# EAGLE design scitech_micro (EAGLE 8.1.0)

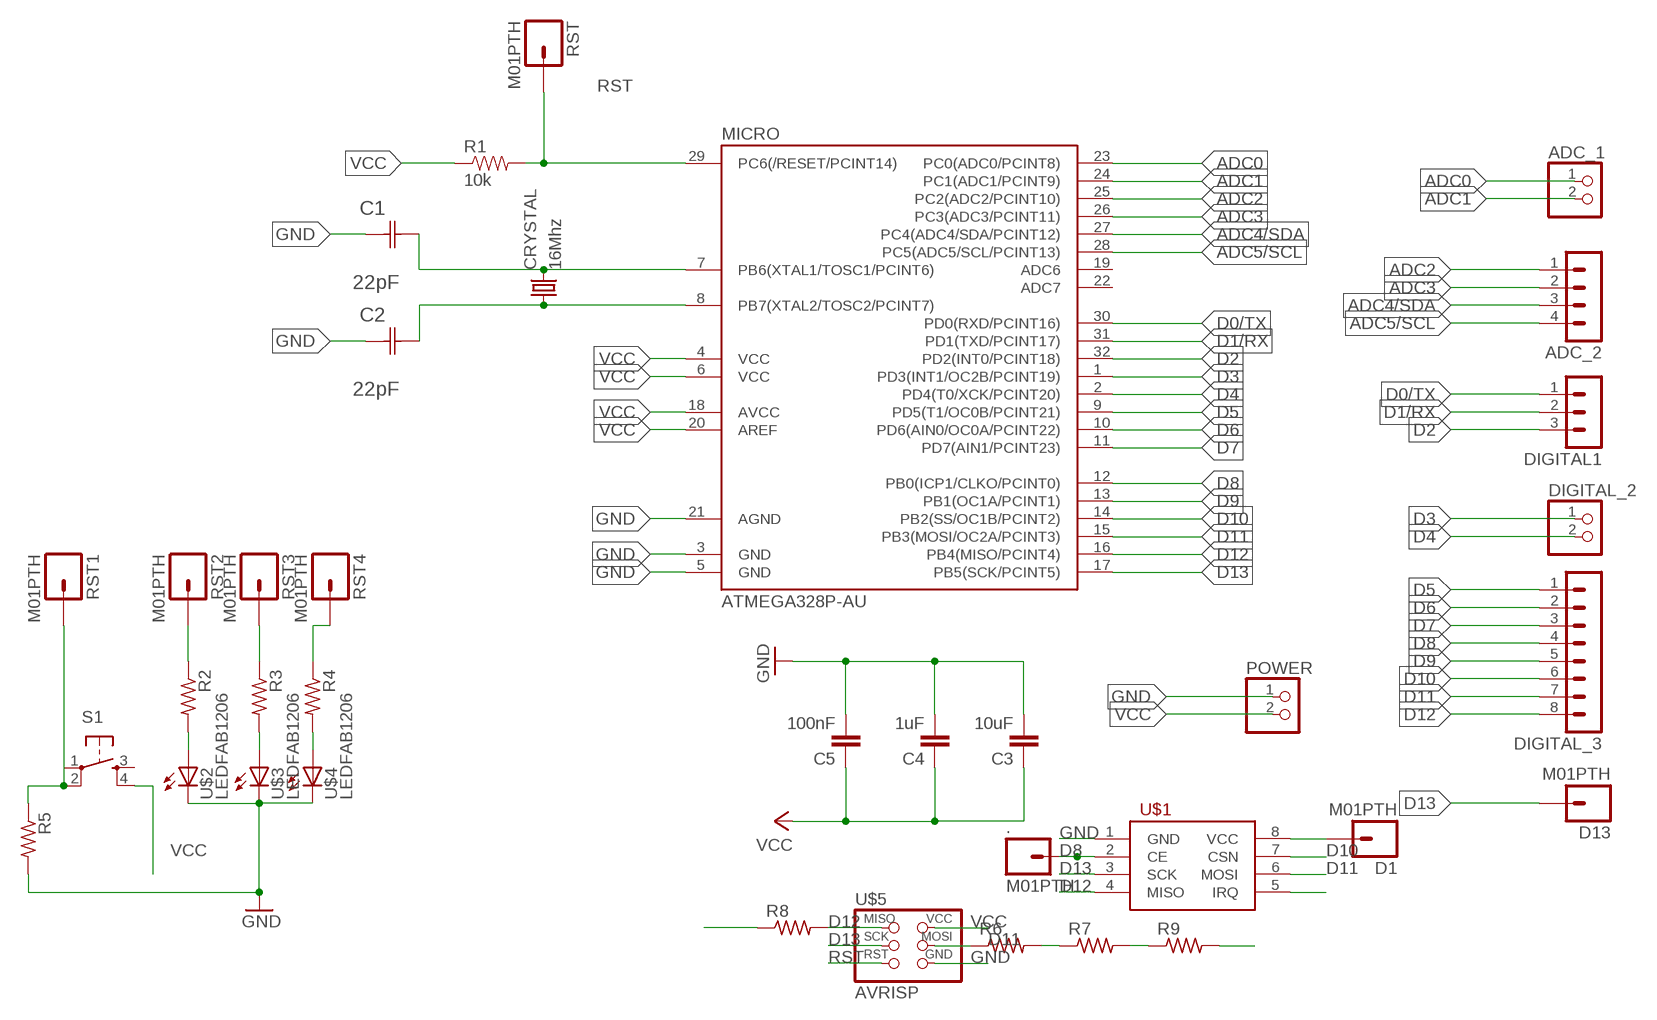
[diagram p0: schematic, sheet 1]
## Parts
.  M01PTH  [1X01]
ADC_1  PINHD-1X2  [1X02]
ADC_2  MA04-1  [MA04-1]
C1  22pF  0612ZC225MAT2A  [CAPC3216X178N]
C2  22pF  0612ZC225MAT2A  [CAPC3216X178N]
C3  10uF  CAP1206  [1206]
C4  1uF  CAP1206  [1206]
C5  100nF  CAP1206  [1206]
CRYSTAL  16Mhz  CSM-7X-DU  [CSM-7X-DU]
D1  M01PTH  [1X01]
D13  M01PTH  [1X01]
DIGITAL1  MA03-1  [MA03-1]
DIGITAL_2  PINHD-1X2  [1X02]
DIGITAL_3  MA08-1  [MA08-1]
MICRO  ATMEGA328P-AU  ATMEGA48/88/168-AU  [TQFP32-08]
POWER  PINHD-1X2  [1X02]
R1  10k  RESISTOR1206  [1206]
R2  RES-US1206FAB  [R1206FAB]
R3  RES-US1206FAB  [R1206FAB]
R4  RES-US1206FAB  [R1206FAB]
R5  RES-US1206FAB  [R1206FAB]
R6  RES-US1206FAB  [R1206FAB]
R7  RES-US1206FAB  [R1206FAB]
R8  RES-US1206FAB  [R1206FAB]
R9  RES-US1206FAB  [R1206FAB]
RST  M01PTH  [1X01]
RST1  M01PTH  [1X01]
RST2  M01PTH  [1X01]
RST3  M01PTH  [1X01]
RST4  M01PTH  [1X01]
S1  6MM_SWITCH6MM_SWITCH  [6MM_SWITCH]
U$1  NRF24L01+  [2X04_THRU]
U$2  LEDFAB1206  [LED1206FAB]
U$3  LEDFAB1206  [LED1206FAB]
U$4  LEDFAB1206  [LED1206FAB]
U$5  AVRISP  [2X03]

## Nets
ADC0: ADC_1.1 MICRO.23(PC0(ADC0/PCINT8))
ADC1: ADC_1.2 MICRO.24(PC1(ADC1/PCINT9))
ADC2: ADC_2.1 MICRO.25(PC2(ADC2/PCINT10))
ADC3: ADC_2.2 MICRO.26(PC3(ADC3/PCINT11))
ADC4/SDA: ADC_2.3 MICRO.27(PC4(ADC4/SDA/PCINT12))
ADC5/SCL: ADC_2.4 MICRO.28(PC5(ADC5/SCL/PCINT13))
D0/TX: DIGITAL1.1 MICRO.30(PD0(RXD/PCINT16))
D1/RX: DIGITAL1.2 MICRO.31(PD1(TXD/PCINT17))
D2: DIGITAL1.3 MICRO.32(PD2(INT0/PCINT18))
D3: DIGITAL_2.1 MICRO.1(PD3(INT1/OC2B/PCINT19))
D4: DIGITAL_2.2 MICRO.2(PD4(T0/XCK/PCINT20))
D5: DIGITAL_3.1 MICRO.9(PD5(T1/OC0B/PCINT21))
D6: DIGITAL_3.2 MICRO.10(PD6(AIN0/OC0A/PCINT22))
D7: DIGITAL_3.3 MICRO.11(PD7(AIN1/PCINT23))
D8: ..1 DIGITAL_3.4 MICRO.12(PB0(ICP1/CLKO/PCINT0)) U$1.2(CE)
D9: DIGITAL_3.5 MICRO.13(PB1(OC1A/PCINT1))
D10: DIGITAL_3.6 MICRO.14(PB2(SS/OC1B/PCINT2)) U$1.7(CSN)
D11: DIGITAL_3.7 MICRO.15(PB3(MOSI/OC2A/PCINT3)) R6.1 R9.2 U$1.6(MOSI) U$5.4(MOSI)
D12: DIGITAL_3.8 MICRO.16(PB4(MISO/PCINT4)) R8.1 R8.2 U$1.4(MISO) U$5.1(MISO)
D13: D13.1 MICRO.17(PB5(SCK/PCINT5)) U$1.3(SCK) U$5.3(SCK)
GND: C1.1(C1) C2.1(C1) C3.2 C4.2 C5.2 MICRO.3(GND) MICRO.5(GND) MICRO.21(AGND) POWER.1 R5.2 U$1.1(GND) U$2.2(C) U$3.2(C) U$4.2(C) U$5.6(GND)
N$1: R2.1 RST2.1
N$2: C1.2(C2) CRYSTAL.2 MICRO.7(PB6(XTAL1/TOSC1/PCINT6))
N$3: R6.2 R7.1
N$4: R3.1 RST3.1
N$5: R4.1 RST4.1
N$6: R2.2 U$2.1(A)
N$7: R3.2 U$3.1(A)
N$8: R4.2 U$4.1(A)
N$9: C2.2(C2) CRYSTAL.1 MICRO.8(PB7(XTAL2/TOSC2/PCINT7))
N$10: R5.1 RST1.1 S1.2(P1)
N$11: R7.2 R9.1
N$15: D1.1 U$1.8(VCC)
N$18: U$1.5(IRQ)
RST: MICRO.29(PC6(/RESET/PCINT14)) R1.2 RST.1 U$5.5(RST)
VCC: C3.1 C4.1 C5.1 MICRO.4(VCC) MICRO.6(VCC) MICRO.18(AVCC) MICRO.20(AREF) POWER.2 R1.1 S1.4(S1) U$5.2(VCC)
Unconnected: MICRO.19(ADC6) MICRO.22(ADC7) S1.1(P) S1.3(S)

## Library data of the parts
. D1 D13 RST RST1-RST4 = 01_SparkFun:M01: Header 1
ADC_1 DIGITAL_2 POWER = pinhead:PINHD-1X2: PIN HEADER
ADC_2 = con-lstb:MA04-1: PIN HEADER; OC_FARNELL: unknown; OC_NEWARK: unknown
C1 C2 = AVX_By_element14_Batch_1:0612ZC225MAT2A: Capacitor 1206; MPN: 0612ZC225MAT2A; OC_FARNELL: -; OC_NEWARK: 12N3209; SUPPLIER: AVX; TOLERANCE: ±20%; VALUE: 2.2µF; VOLTAGERATING: 10V
C3-C5 = 01_SparkFun:CAP: Capacitor
CRYSTAL = 01_FAB_Hello:CSM-7X-DU: SMD CRYSTAL; OC_FARNELL: unknown; OC_NEWARK: unknown
DIGITAL1 = con-lstb:MA03-1: PIN HEADER; OC_FARNELL: unknown; OC_NEWARK: unknown
DIGITAL_3 = con-lstb:MA08-1: PIN HEADER; OC_FARNELL: unknown; OC_NEWARK: unknown
MICRO = atmega8:ATMEGA48/88/168
R1 = 01_SparkFun:RESISTOR: Resistor
R2-R9 = fab:RES-US: Resistor (US Symbol)
S1 = fab:6MM_SWITCH: OMRON SWITCH
U$1 = fab:NRF24L01+: nRF24L01+ 2.4GHz Wireless Transceiver module
U$2-U$4 = fab:LED: LED
U$5 = fab:AVRISP

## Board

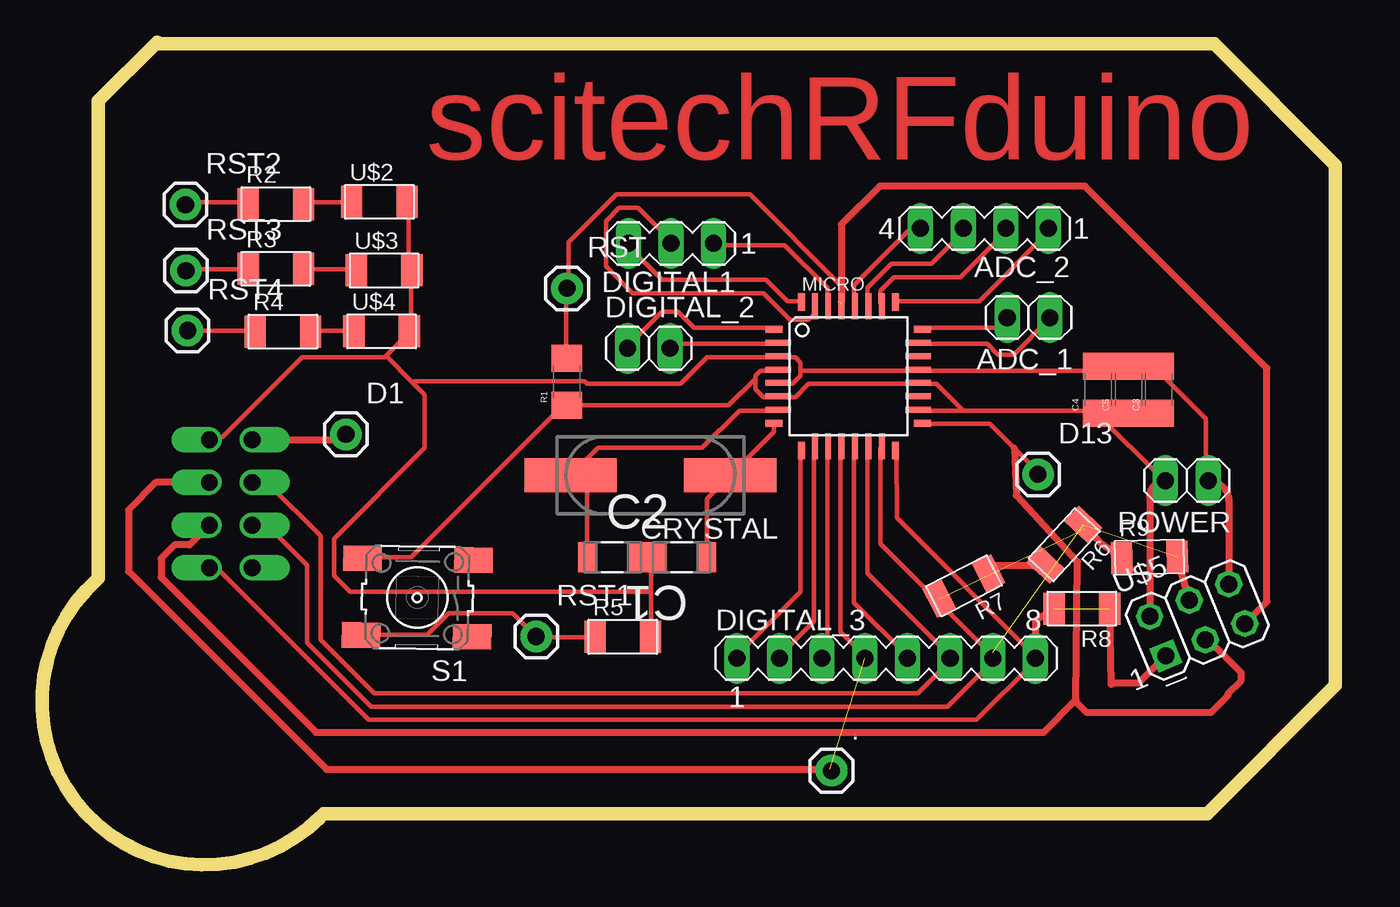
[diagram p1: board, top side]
Size 77.02 x 48.98 mm. Coordinates in mm from the lower left corner, seen from the top.
Outline: 6.85,48.87 69.8,48.87 77.02,41.66 77.02,10.7 69.38,3.06 16.78,3.06 16.56,2.84 arc-184 3.36,17.06 3.36,45.49 6.85,48.98
Copper layers (1*16): Top 0.035mm / dielectric 1.5mm / Bottom 0.035mm
Design rules "default *": minimum track width 10mil, minimum drill 24mil, track to track 16mil, track to pad 16mil, pad to pad 16mil, via to via 16mil, smd to smd 8mil, copper to edge 40mil, drill to drill 16mil, minimum pad ring 10mil, minimum via ring 8mil, stop-mask expansion 4mil, vias tented up to drill 0mil, thermal gap 10mil

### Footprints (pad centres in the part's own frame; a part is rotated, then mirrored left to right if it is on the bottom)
1X01 = drill 1.016 pad 1.88: 1 0,0
1X02 = drill 1.016 long: 1 -1.27,0; 2 1.27,0
MA04-1 = drill 1.016 long: 1 -3.81,0; 2 -1.27,0; 3 1.27,0; 4 3.81,0
CAPC3216X178N = smd 1.118 x 1.803: 1 -1.499,0; 2 1.499,0
1206 = smd 1.6 x 1.8: 1 -1.4,0; 2 1.4,0
CSM-7X-DU = smd 5.5 x 2: 1 -4.75,0; 2 4.75,0
MA03-1 = drill 1.016 long: 1 -2.54,0; 2 0,0; 3 2.54,0
MA08-1 = drill 1.016 long: 1 -8.89,0; 2 -6.35,0; 3 -3.81,0; 4 -1.27,0; 5 1.27,0; 6 3.81,0; 7 6.35,0; 8 8.89,0
TQFP32-08 = smd 1.016 x 0.406: 1 -4.42,2.8; 8 -4.42,-2.8; 17 4.42,-2.8; 24 4.42,2.8 | smd 1.524 x 0.356: 2 -4.166,2; 3 -4.166,1.2; 4 -4.166,0.4; 5 -4.166,-0.4; 6 -4.166,-1.2; 7 -4.166,-2; 18 4.166,-2; 19 4.166,-1.2; 20 4.166,-0.4; 21 4.166,0.4; 22 4.166,1.2; 23 4.166,2 | smd 0.406 x 1.016: 9 -2.8,-4.42; 16 2.8,-4.42; 25 2.8,4.42; 32 -2.8,4.42 | smd 0.356 x 1.524: 10 -2,-4.166; 11 -1.2,-4.166; 12 -0.4,-4.166; 13 0.4,-4.166; 14 1.2,-4.166; 15 2,-4.166; 26 2,4.166; 27 1.2,4.166; 28 0.4,4.166; 29 -0.4,4.166; 30 -1.2,4.166; 31 -2,4.166
R1206FAB = smd 1.27 x 1.905: 1 -1.651,0; 2 1.651,0
6MM_SWITCH = smd 2.286 x 1.524: 1 -3.302,2.286; 2 3.302,2.286; 3 -3.302,-2.286; 4 3.302,-2.286
2X04_THRU = drill 1 offset: 1 -1.27,3.81; 2 -1.27,1.27; 3 -1.27,-1.27; 4 -1.27,-3.81; 5 1.27,-3.81; 6 1.27,-1.27; 7 1.27,1.27; 8 1.27,3.81
LED1206FAB = smd 1.27 x 1.905: 1 -1.651,0; 2 1.651,0
2X03 = drill 1.016 square: 1 -2.54,-1.27 | drill 1.016 octagon: 2 -2.54,1.27; 3 0,-1.27; 4 0,1.27; 5 2.54,-1.27; 6 2.54,1.27

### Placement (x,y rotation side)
.  47,5.61 0 top
ADC_1  58.74,32.58 180 top
ADC_2  56.12,37.89 180 top
C1  33.97,18.32 180 top
C2  38.08,18.32 0 top
C3  66.49,28.29 90 top
C4  62.88,28.29 90 top
C5  64.69,28.29 90 top
CRYSTAL  36.22,23.2 180 top
D1  18.1,25.63 0 top
D13  59.3,23.25 0 top
DIGITAL1  37.45,37 180 top
DIGITAL_2  36.13,30.75 0 top
DIGITAL_3  50.26,12.3 0 top
MICRO  48.01,29.09 0 top
POWER  68.16,22.87 180 top
R1  31.25,28.76 90 top
R2  13.93,39.33 0 top
R3  13.93,35.48 0 top
R4  14.35,31.74 0 top
R5  34.58,13.58 0 top
R6  60.87,19.05 227.1 top
R7  54.9,16.61 207.3 top
R8  61.92,15.25 180 top
R9  65.94,18.32 1.3 top
RST  31.26,34.31 0 top
RST1  29.43,13.6 0 top
RST2  8.54,39.3 0 top
RST3  8.57,35.37 0 top
RST4  8.66,31.81 0 top
S1  22.34,15.91 179.1 top
U$1  11.24,21.5 0 top
U$2  20.09,39.46 0 top
U$3  20.37,35.38 0 top
U$4  20.22,31.76 0 top
U$5  68.79,14.58 22.2 top

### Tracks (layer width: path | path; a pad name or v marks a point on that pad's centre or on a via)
ADC0
  Top 0.254: MICRO.23 52.31,31.02 56.28,31.02 56.91,30.38 57.87,30.38 59.93,32.44 ADC_1.1
ADC1
  Top 0.254: MICRO.24 52.47,31.97 56.91,31.97 57.39,32.44 ADC_1.2
ADC2
  Top 0.254: ADC_2.1 59.93,37.68 55.8,33.56 50.88,33.56 MICRO.25
ADC3
  Top 0.254: ADC_2.2 57.39,37.68 54.69,34.98 50.72,34.98 49.93,34.19 49.93,33.4 MICRO.26
ADC4/SDA
  Top 0.254: ADC_2.3 54.85,37.68 52.94,35.78 50.56,35.78 49.13,34.35 49.13,33.4 MICRO.27
ADC5/SCL
  Top 0.254: MICRO.28 48.34,33.4 48.34,34.51 51.67,37.84 52.31,37.84 ADC_2.4
D0/TX
  Top 0.254: MICRO.30 46.75,33.4 46.75,34.35 44.21,36.89 40.09,36.89 DIGITAL1.1
D1/RX
  Top 0.254: MICRO.31 45.96,33.24 45.96,32.76 45.64,32.44 44.53,32.44 42.94,34.03 35.16,34.03 33.58,35.62 33.58,38.32 34.37,39.11 35.48,39.11 37.55,37.05 DIGITAL1.2
D2
  Top 0.254: MICRO.32 45.17,33.56 44.37,33.56 43.1,34.83 36.91,34.83 34.85,36.89 DIGITAL1.3
D3
  Top 0.254: MICRO.1 43.58,31.97 38.82,31.97 37.86,32.92 36.91,32.92 34.85,30.86 DIGITAL_2.1
D4
  Top 0.254: MICRO.2 43.74,31.02 37.7,31.02 37.55,30.86 DIGITAL_2.2
D5
  Top 0.254: MICRO.9 45.17,24.67 45.17,16.25 41.36,12.44 DIGITAL_3.1
D6
  Top 0.254: MICRO.10 45.96,24.82 45.96,14.51 43.9,12.44 DIGITAL_3.2
D7
  Top 0.254: MICRO.11 46.75,24.82 46.75,12.6 46.59,12.44 DIGITAL_3.3
D8  (1 unrouted)
  Top 0.254: MICRO.12 47.55,24.82 47.55,13.87 48.98,12.44 DIGITAL_3.4
  Top 0.406: U$1.2 6.78,22.77 5.16,21.14 5.16,17.48 16.94,5.69 46.92,5.69 ..1
D9
  Top 0.254: MICRO.13 48.34,24.82 48.34,15.62 51.52,12.44 DIGITAL_3.5
D10
  Top 0.254: MICRO.14 49.13,24.82 49.13,17.36 54.06,12.44 DIGITAL_3.6 54.21,12.28 52.15,10.22 19.77,10.22 16.59,13.39 16.59,19.59 13.42,22.76 12.62,22.76 U$1.7
D11  (2 unrouted)
  Top 0.254: MICRO.15 49.93,24.82 49.93,19.11 56.6,12.44 DIGITAL_3.7 56.75,12.28 53.9,9.43 19.61,9.43 15.8,13.24 15.8,17.84 13.42,20.22 12.62,20.22 U$1.6
  Top 0.406: DIGITAL_3.7 56.61,12.67 | U$5.4 R9.2
D12  (1 unrouted)
  Top 0.254: MICRO.16 50.88,24.67 50.91,20.66 59.16,12.4 DIGITAL_3.8 | 59.12,12.1 55.64,8.63 19.45,8.63 10.4,17.68 10.08,17.68 U$1.4
  Top 0.406: 59.12,12.1 59.12,12.26 DIGITAL_3.8 59.15,14.54 R8.2 | U$5.1 65.29,10.82 63.88,10.82 63.66,10.74 R8.1
D13
  Top 0.254: MICRO.17 52.47,26.25 56.44,26.25 57.88,24.81 59.29,23.4 D13.1
  Top 0.406: U$1.3 8.79,19.05 7.89,19.05 7.09,18.25 7.09,17.12 16.32,7.89 18.67,7.89 59.64,7.89 61.51,9.76 | 57.88,24.81 58.01,22 61.65,18.06 61.56,9.82 61.51,9.76 | 61.51,9.76 62.2,9.08 69.61,9.08 70.61,10.08 70.61,10.19 71.4,10.98 71.4,11.45 69.45,13.4 U$5.3
GND
  Top 0.254: 45.17,29.43 45.17,29.9 44.85,30.22 43.9,30.22 MICRO.3 43.74,30.22 39.61,30.22 38.02,28.63 32.47,28.63 32.31,28.79 22.15,28.79 22.07,28.71 | 45.17,29.43 45.17,29.11 44.69,28.63 43.9,28.63 MICRO.5 | 45.17,29.43 52.15,29.43 MICRO.21 52.31,29.43 62.63,29.43 62.79,29.59 C4.2 62.95,29.75 64.53,29.75 C5.2 64.69,29.75 66.44,29.75 C3.2 66.6,29.59 66.6,29.27 69.3,26.57 69.3,22.92 POWER.1 | 36.28,18.32 36.43,18.32 C2.1 36.28,18.32 | 36.28,18.32 35.48,18.32 C1.1 | 36.28,18.32 36.28,16.25 | 36.28,16.25 36.28,13.71 R5.2 | U$2.2 21.83,39.43 21.83,35.62 21.99,35.46 U$3.2 21.99,35.3 21.99,31.81 U$4.2 21.83,31.65 20.48,30.3 | 20.48,30.3 20.4,30.22 15.48,30.22 10.72,25.46 10.08,25.46 U$1.1 | 36.28,16.25 18.34,16.25 17.38,17.2 17.38,19.43 22.78,24.82 22.78,28 22.07,28.71 | 20.48,30.3 22.07,28.71
  Top 0.406: POWER.1 arc-90 70.66,21.65 U$5.6
N$1
  Top 0.254: R2.1 12.15,39.43 8.65,39.43 RST2.1
N$2
  Top 0.254: MICRO.7 43.74,27.05 41.51,27.05 39.29,24.82 33.1,24.82 31.51,23.24 CRYSTAL.2 32.47,24.03 32.47,18.47 C1.2
N$3
  Top 0.406: R7.1 56.36,17.84 R6.2
N$4
  Top 0.254: R3.1 12.15,35.46 8.65,35.46 RST3.1
N$5
  Top 0.254: R4.1 12.62,31.81 8.81,31.81 RST4.1
N$6
  Top 0.254: R2.2 15.64,39.43 18.34,39.43 U$2.1
N$7
  Top 0.254: R3.2 15.64,35.46 18.65,35.46 U$3.1
N$8
  Top 0.254: R4.2 16.11,31.81 18.5,31.81 U$4.1
N$9
  Top 0.254: MICRO.8 43.58,26.25 43.58,25.78 41.04,23.24 CRYSTAL.1 40.88,23.08 39.61,21.81 39.61,18.47 C2.2
N$10
  Top 0.254: R5.1 32.78,13.55 29.45,13.55 RST1.1 29.29,13.71 28.02,14.98 24.21,14.98 22.94,13.71 19.13,13.71 S1.2
N$11  (1 unrouted)
  Top 0.406: R9.1 63.07,19.13 arc10 62.1,20.02 arc-105 62.1,20.26
N$15
  Top 0.406: U$1.8 17.77,25.31 D1.1
RST  (1 unrouted)
  Top 0.254: MICRO.29 47.55,33.4 47.55,34.51 42.15,39.91 34.21,39.91 31.35,37.05 31.35,34.35 RST.1 31.2,34.19 31.2,30.22 R1.2
  Top 0.406: U$5.5 72.93,15.67 72.93,29.57 62.1,40.4 49.88,40.4 47.6,38.12 47.6,33.5
VCC
  Top 0.254: 54.85,27.05 62.79,27.05 C4.1 | 54.85,27.05 52.31,27.05 MICRO.18 | 54.85,27.05 53.26,28.63 52.31,28.63 MICRO.20 52.15,28.63 45.64,28.63 44.85,27.84 43.9,27.84 MICRO.6 43.74,27.84 42.94,27.84 42.47,28.32 42.47,28.95 | C4.1 62.95,26.89 64.53,26.89 C5.1 66.44,26.89 C3.1 | POWER.2 66.76,22.92 62.79,26.89 C4.1 | 42.47,28.95 42.47,29.11 42.78,29.43 43.74,29.43 MICRO.4 | 42.47,28.95 40.88,27.36 31.35,27.36 R1.1 31.2,27.21 30.88,27.21 21.99,18.32 19.13,18.32 S1.4
  Top 0.406: POWER.2 arc90 65.96,21.94 U$5.2

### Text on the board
Top: scitechRFduino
